VERSION 5.7 ;
  NOWIREEXTENSIONATPIN ON ;
  DIVIDERCHAR "/" ;
  BUSBITCHARS "[]" ;
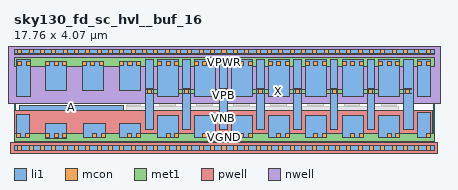
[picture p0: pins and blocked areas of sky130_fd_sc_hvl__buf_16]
MACRO sky130_fd_sc_hvl__buf_16
  CLASS BLOCK ;
  FOREIGN sky130_fd_sc_hvl__buf_16 ;
  ORIGIN 0.000 0.000 ;
  SIZE 17.760 BY 4.070 ;
  PIN A
    ANTENNAGATEAREA 6.750000 ;
    PORT
      LAYER li1 ;
        RECT 0.220 1.580 4.630 1.815 ;
    END
  END A
  PIN VGND
    USE GROUND ;
    PORT
      LAYER li1 ;
        RECT 0.110 0.425 0.645 1.410 ;
        RECT 1.340 0.415 2.230 1.025 ;
        RECT 2.960 0.425 3.855 1.025 ;
        RECT 4.440 0.425 5.330 1.025 ;
        RECT 6.070 0.425 6.960 1.395 ;
        RECT 7.630 0.425 8.520 1.395 ;
        RECT 9.190 0.425 10.080 1.395 ;
        RECT 10.750 0.425 11.640 1.395 ;
        RECT 12.310 0.425 13.200 1.395 ;
        RECT 13.870 0.425 14.760 1.395 ;
        RECT 15.430 0.425 16.320 1.395 ;
        RECT 17.070 0.425 17.600 1.495 ;
      LAYER mcon ;
        RECT 0.115 0.425 0.285 0.595 ;
        RECT 0.475 0.425 0.645 0.595 ;
        RECT 1.340 0.425 1.510 0.595 ;
        RECT 1.700 0.425 1.870 0.595 ;
        RECT 2.060 0.425 2.230 0.595 ;
        RECT 3.320 0.425 3.490 0.595 ;
        RECT 3.680 0.425 3.850 0.595 ;
        RECT 4.800 0.425 4.970 0.595 ;
        RECT 5.160 0.425 5.330 0.595 ;
        RECT 6.430 0.425 6.600 0.595 ;
        RECT 6.790 0.425 6.960 0.595 ;
        RECT 7.990 0.425 8.160 0.595 ;
        RECT 8.350 0.425 8.520 0.595 ;
        RECT 9.550 0.425 9.720 0.595 ;
        RECT 9.910 0.425 10.080 0.595 ;
        RECT 11.110 0.425 11.280 0.595 ;
        RECT 11.470 0.425 11.640 0.595 ;
        RECT 12.670 0.425 12.840 0.595 ;
        RECT 13.030 0.425 13.200 0.595 ;
        RECT 14.230 0.425 14.400 0.595 ;
        RECT 14.590 0.425 14.760 0.595 ;
        RECT 15.790 0.425 15.960 0.595 ;
        RECT 16.150 0.425 16.320 0.595 ;
        RECT 17.430 0.425 17.600 0.595 ;
      LAYER met1 ;
        RECT 0.000 0.255 17.760 0.625 ;
    END
  END VGND
  PIN VNB
    ANTENNADIFFAREA 3.019200 ;
    PORT
      LAYER pwell ;
        RECT 0.020 0.215 17.690 1.585 ;
        RECT -0.130 -0.215 17.890 0.215 ;
      LAYER li1 ;
        RECT 0.000 -0.085 17.760 0.085 ;
      LAYER mcon ;
        RECT 0.155 -0.085 0.325 0.085 ;
        RECT 0.635 -0.085 0.805 0.085 ;
        RECT 1.115 -0.085 1.285 0.085 ;
        RECT 1.595 -0.085 1.765 0.085 ;
        RECT 2.075 -0.085 2.245 0.085 ;
        RECT 2.555 -0.085 2.725 0.085 ;
        RECT 3.035 -0.085 3.205 0.085 ;
        RECT 3.515 -0.085 3.685 0.085 ;
        RECT 3.995 -0.085 4.165 0.085 ;
        RECT 4.475 -0.085 4.645 0.085 ;
        RECT 4.955 -0.085 5.125 0.085 ;
        RECT 5.435 -0.085 5.605 0.085 ;
        RECT 5.915 -0.085 6.085 0.085 ;
        RECT 6.395 -0.085 6.565 0.085 ;
        RECT 6.875 -0.085 7.045 0.085 ;
        RECT 7.355 -0.085 7.525 0.085 ;
        RECT 7.835 -0.085 8.005 0.085 ;
        RECT 8.315 -0.085 8.485 0.085 ;
        RECT 8.795 -0.085 8.965 0.085 ;
        RECT 9.275 -0.085 9.445 0.085 ;
        RECT 9.755 -0.085 9.925 0.085 ;
        RECT 10.235 -0.085 10.405 0.085 ;
        RECT 10.715 -0.085 10.885 0.085 ;
        RECT 11.195 -0.085 11.365 0.085 ;
        RECT 11.675 -0.085 11.845 0.085 ;
        RECT 12.155 -0.085 12.325 0.085 ;
        RECT 12.635 -0.085 12.805 0.085 ;
        RECT 13.115 -0.085 13.285 0.085 ;
        RECT 13.595 -0.085 13.765 0.085 ;
        RECT 14.075 -0.085 14.245 0.085 ;
        RECT 14.555 -0.085 14.725 0.085 ;
        RECT 15.035 -0.085 15.205 0.085 ;
        RECT 15.515 -0.085 15.685 0.085 ;
        RECT 15.995 -0.085 16.165 0.085 ;
        RECT 16.475 -0.085 16.645 0.085 ;
        RECT 16.955 -0.085 17.125 0.085 ;
        RECT 17.435 -0.085 17.605 0.085 ;
      LAYER met1 ;
        RECT 0.000 -0.115 17.760 0.115 ;
    END
  END VNB
  PIN VPB
    ANTENNADIFFAREA 3.019200 ;
    PORT
      LAYER nwell ;
        RECT -0.330 1.885 18.090 4.485 ;
      LAYER li1 ;
        RECT 0.000 3.985 17.760 4.155 ;
      LAYER mcon ;
        RECT 0.155 3.985 0.325 4.155 ;
        RECT 0.635 3.985 0.805 4.155 ;
        RECT 1.115 3.985 1.285 4.155 ;
        RECT 1.595 3.985 1.765 4.155 ;
        RECT 2.075 3.985 2.245 4.155 ;
        RECT 2.555 3.985 2.725 4.155 ;
        RECT 3.035 3.985 3.205 4.155 ;
        RECT 3.515 3.985 3.685 4.155 ;
        RECT 3.995 3.985 4.165 4.155 ;
        RECT 4.475 3.985 4.645 4.155 ;
        RECT 4.955 3.985 5.125 4.155 ;
        RECT 5.435 3.985 5.605 4.155 ;
        RECT 5.915 3.985 6.085 4.155 ;
        RECT 6.395 3.985 6.565 4.155 ;
        RECT 6.875 3.985 7.045 4.155 ;
        RECT 7.355 3.985 7.525 4.155 ;
        RECT 7.835 3.985 8.005 4.155 ;
        RECT 8.315 3.985 8.485 4.155 ;
        RECT 8.795 3.985 8.965 4.155 ;
        RECT 9.275 3.985 9.445 4.155 ;
        RECT 9.755 3.985 9.925 4.155 ;
        RECT 10.235 3.985 10.405 4.155 ;
        RECT 10.715 3.985 10.885 4.155 ;
        RECT 11.195 3.985 11.365 4.155 ;
        RECT 11.675 3.985 11.845 4.155 ;
        RECT 12.155 3.985 12.325 4.155 ;
        RECT 12.635 3.985 12.805 4.155 ;
        RECT 13.115 3.985 13.285 4.155 ;
        RECT 13.595 3.985 13.765 4.155 ;
        RECT 14.075 3.985 14.245 4.155 ;
        RECT 14.555 3.985 14.725 4.155 ;
        RECT 15.035 3.985 15.205 4.155 ;
        RECT 15.515 3.985 15.685 4.155 ;
        RECT 15.995 3.985 16.165 4.155 ;
        RECT 16.475 3.985 16.645 4.155 ;
        RECT 16.955 3.985 17.125 4.155 ;
        RECT 17.435 3.985 17.605 4.155 ;
      LAYER met1 ;
        RECT 0.000 3.955 17.760 4.185 ;
    END
  END VPB
  PIN VPWR
    USE POWER ;
    PORT
      LAYER li1 ;
        RECT 0.110 2.175 0.680 3.755 ;
        RECT 1.340 2.445 2.230 3.675 ;
        RECT 2.880 2.445 3.770 3.675 ;
        RECT 4.460 2.445 5.350 3.675 ;
        RECT 6.070 2.175 6.960 3.755 ;
        RECT 7.630 2.175 8.520 3.755 ;
        RECT 9.190 2.175 10.080 3.755 ;
        RECT 10.750 2.175 11.640 3.755 ;
        RECT 12.310 2.175 13.200 3.755 ;
        RECT 13.870 2.175 14.760 3.755 ;
        RECT 15.430 2.175 16.320 3.755 ;
        RECT 17.070 2.175 17.600 3.755 ;
      LAYER mcon ;
        RECT 0.150 3.475 0.320 3.645 ;
        RECT 0.510 3.475 0.680 3.645 ;
        RECT 1.340 3.475 1.510 3.645 ;
        RECT 1.700 3.475 1.870 3.645 ;
        RECT 2.060 3.475 2.230 3.645 ;
        RECT 2.880 3.475 3.050 3.645 ;
        RECT 3.240 3.475 3.410 3.645 ;
        RECT 3.600 3.475 3.770 3.645 ;
        RECT 4.460 3.475 4.630 3.645 ;
        RECT 4.820 3.475 4.990 3.645 ;
        RECT 5.180 3.475 5.350 3.645 ;
        RECT 6.070 3.475 6.240 3.645 ;
        RECT 6.430 3.475 6.600 3.645 ;
        RECT 6.790 3.475 6.960 3.645 ;
        RECT 7.630 3.475 7.800 3.645 ;
        RECT 7.990 3.475 8.160 3.645 ;
        RECT 8.350 3.475 8.520 3.645 ;
        RECT 9.190 3.475 9.360 3.645 ;
        RECT 9.550 3.475 9.720 3.645 ;
        RECT 9.910 3.475 10.080 3.645 ;
        RECT 10.750 3.475 10.920 3.645 ;
        RECT 11.110 3.475 11.280 3.645 ;
        RECT 11.470 3.475 11.640 3.645 ;
        RECT 12.310 3.475 12.480 3.645 ;
        RECT 12.670 3.475 12.840 3.645 ;
        RECT 13.030 3.475 13.200 3.645 ;
        RECT 13.870 3.475 14.040 3.645 ;
        RECT 14.230 3.475 14.400 3.645 ;
        RECT 14.590 3.475 14.760 3.645 ;
        RECT 15.430 3.475 15.600 3.645 ;
        RECT 15.790 3.475 15.960 3.645 ;
        RECT 16.150 3.475 16.320 3.645 ;
        RECT 17.070 3.475 17.240 3.645 ;
        RECT 17.430 3.475 17.600 3.645 ;
      LAYER met1 ;
        RECT 0.000 3.445 17.760 3.815 ;
    END
  END VPWR
  PIN X
    ANTENNADIFFAREA 5.040000 ;
    PORT
      LAYER li1 ;
        RECT 5.570 0.790 5.900 3.755 ;
        RECT 7.130 0.790 7.460 3.755 ;
        RECT 8.690 0.790 9.020 3.755 ;
        RECT 10.250 0.790 10.580 3.755 ;
        RECT 11.810 0.790 12.140 3.755 ;
        RECT 13.370 0.790 13.700 3.755 ;
        RECT 14.930 0.790 15.260 3.755 ;
        RECT 16.490 0.790 16.900 3.755 ;
      LAYER mcon ;
        RECT 5.650 2.320 5.820 2.490 ;
        RECT 7.210 2.320 7.380 2.490 ;
        RECT 8.770 2.320 8.940 2.490 ;
        RECT 10.330 2.320 10.500 2.490 ;
        RECT 11.890 2.320 12.060 2.490 ;
        RECT 13.450 2.320 13.620 2.490 ;
        RECT 15.010 2.320 15.180 2.490 ;
        RECT 16.570 2.320 16.740 2.490 ;
      LAYER met1 ;
        RECT 5.590 2.490 5.880 2.520 ;
        RECT 7.150 2.490 7.440 2.520 ;
        RECT 8.710 2.490 9.000 2.520 ;
        RECT 10.270 2.490 10.560 2.520 ;
        RECT 11.830 2.490 12.120 2.520 ;
        RECT 13.390 2.490 13.680 2.520 ;
        RECT 14.950 2.490 15.240 2.520 ;
        RECT 16.510 2.490 16.800 2.520 ;
        RECT 5.590 2.320 16.800 2.490 ;
        RECT 5.590 2.290 5.880 2.320 ;
        RECT 7.150 2.290 7.440 2.320 ;
        RECT 8.710 2.290 9.000 2.320 ;
        RECT 10.270 2.290 10.560 2.320 ;
        RECT 11.830 2.290 12.120 2.320 ;
        RECT 13.390 2.290 13.680 2.320 ;
        RECT 14.950 2.290 15.240 2.320 ;
        RECT 16.510 2.290 16.800 2.320 ;
    END
  END X
  OBS
      LAYER li1 ;
        RECT 0.850 2.265 1.160 3.755 ;
        RECT 2.400 2.265 2.710 3.755 ;
        RECT 3.940 2.265 4.290 3.755 ;
        RECT 0.850 1.985 5.350 2.265 ;
        RECT 4.800 1.410 5.350 1.985 ;
        RECT 6.160 1.565 6.830 1.895 ;
        RECT 7.720 1.565 8.390 1.895 ;
        RECT 9.280 1.565 9.950 1.895 ;
        RECT 10.840 1.565 11.510 1.895 ;
        RECT 12.400 1.565 13.070 1.895 ;
        RECT 13.960 1.565 14.630 1.895 ;
        RECT 15.520 1.565 16.190 1.895 ;
        RECT 0.815 1.195 5.350 1.410 ;
        RECT 0.815 0.755 1.170 1.195 ;
        RECT 2.400 0.730 2.790 1.195 ;
        RECT 4.025 0.730 4.270 1.195 ;
      LAYER mcon ;
        RECT 4.800 1.580 4.970 1.750 ;
        RECT 5.160 1.580 5.330 1.750 ;
        RECT 6.230 1.580 6.400 1.750 ;
        RECT 6.590 1.580 6.760 1.750 ;
        RECT 7.790 1.580 7.960 1.750 ;
        RECT 8.150 1.580 8.320 1.750 ;
        RECT 9.350 1.580 9.520 1.750 ;
        RECT 9.710 1.580 9.880 1.750 ;
        RECT 10.910 1.580 11.080 1.750 ;
        RECT 11.270 1.580 11.440 1.750 ;
        RECT 12.470 1.580 12.640 1.750 ;
        RECT 12.830 1.580 13.000 1.750 ;
        RECT 14.030 1.580 14.200 1.750 ;
        RECT 14.390 1.580 14.560 1.750 ;
        RECT 15.590 1.580 15.760 1.750 ;
        RECT 15.950 1.580 16.120 1.750 ;
      LAYER met1 ;
        RECT 4.740 1.750 5.360 1.780 ;
        RECT 6.170 1.750 6.820 1.780 ;
        RECT 7.730 1.750 8.380 1.780 ;
        RECT 9.290 1.750 9.940 1.780 ;
        RECT 10.850 1.750 11.500 1.780 ;
        RECT 12.410 1.750 13.060 1.780 ;
        RECT 13.970 1.750 14.620 1.780 ;
        RECT 15.530 1.750 16.180 1.780 ;
        RECT 4.740 1.580 16.250 1.750 ;
        RECT 4.740 1.550 5.360 1.580 ;
        RECT 6.170 1.550 6.820 1.580 ;
        RECT 7.730 1.550 8.380 1.580 ;
        RECT 9.290 1.550 9.940 1.580 ;
        RECT 10.850 1.550 11.500 1.580 ;
        RECT 12.410 1.550 13.060 1.580 ;
        RECT 13.970 1.550 14.620 1.580 ;
        RECT 15.530 1.550 16.180 1.580 ;
  END
END sky130_fd_sc_hvl__buf_16
END LIBRARY

